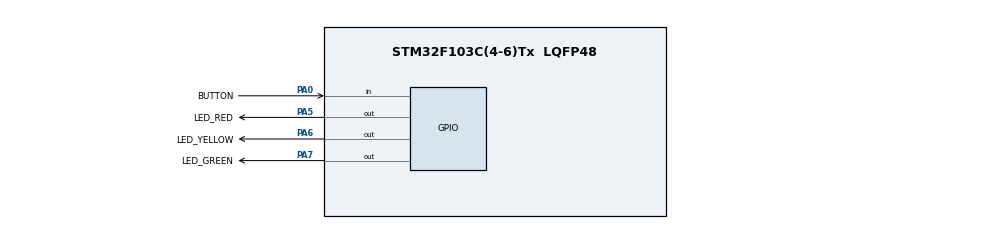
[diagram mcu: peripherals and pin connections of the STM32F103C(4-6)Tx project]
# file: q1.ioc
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Mcu.Family=STM32F1
Mcu.Name=STM32F103C(4-6)Tx
Mcu.Package=LQFP48
NVIC.PriorityGroup=NVIC_PRIORITYGROUP_4
PA0-WKUP.GPIO_Label=BUTTON
PA0-WKUP.Signal=GPIO_Input
PA5.GPIO_Label=LED_RED
PA5.Signal=GPIO_Output
PA6.GPIO_Label=LED_YELLOW
PA6.Signal=GPIO_Output
PA7.GPIO_Label=LED_GREEN
PA7.Signal=GPIO_Output
ProjectManager.HeapSize=0x200
ProjectManager.StackSize=0x400
ProjectManager.TargetToolchain=STM32CubeIDE
RCC.AHBCLKDivider=RCC_SYSCLK_DIV2
RCC.AHBFreq_Value=10000000
RCC.APB1Freq_Value=10000000
RCC.APB1TimFreq_Value=10000000
RCC.APB2Freq_Value=10000000
RCC.APB2TimFreq_Value=10000000
RCC.HCLKFreq_Value=10000000
RCC.PLLMUL=RCC_PLL_MUL5
RCC.SYSCLKFreq_VALUE=20000000
RCC.SYSCLKSource=RCC_SYSCLKSOURCE_PLLCLK
RCC.USBFreq_Value=20000000
board=custom

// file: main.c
/* USER CODE BEGIN Header */
/**
  ******************************************************************************
  * @file           : main.c
  * @brief          : Main program body
  ******************************************************************************
  * @attention
  *
  * Copyright (c) 2025 STMicroelectronics.
  * All rights reserved.
  *
  * This software is licensed under terms that can be found in the LICENSE file
  * in the root directory of this software component.
  * If no LICENSE file comes with this software, it is provided AS-IS.
  *
  ******************************************************************************
  */
/* USER CODE END Header */
#include "main.h"

void SystemClock_Config(void);
static void MX_GPIO_Init(void);

int main(void)
{

  /* MCU Configuration--------------------------------------------------------*/

  /* Reset of all peripherals, Initializes the Flash interface and the Systick. */
  HAL_Init();

  /* Configure the system clock */
  SystemClock_Config();

  /* Initialize all configured peripherals */
  MX_GPIO_Init();
  /* USER CODE BEGIN 2 */

  	uint8_t led_state = 0;
  	uint8_t button_pressed = 0;
  	uint8_t last_button_state = 1;

  /* USER CODE END 2 */

  /* Infinite loop */
  while (1)
  {
	  uint8_t current_button_state = HAL_GPIO_ReadPin(GPIOA, GPIO_PIN_0);

	    		if (current_button_state == 0 && last_button_state == 1)
	    		{
	    			button_pressed = 1;
	    		}
	    		last_button_state = current_button_state;

	    		if (button_pressed)
	    		{
	    			button_pressed = 0;
	    			led_state = (led_state + 1) % 3;

	    			HAL_GPIO_WritePin(GPIOA, GPIO_PIN_5 | GPIO_PIN_6 | GPIO_PIN_7, GPIO_PIN_RESET);

	    			switch (led_state)
	    			{
	    			case 0:
	    				HAL_GPIO_WritePin(GPIOA, GPIO_PIN_5, GPIO_PIN_SET);
	    				break;
	    			case 1:
	    				HAL_GPIO_WritePin(GPIOA, GPIO_PIN_7, GPIO_PIN_SET);
	    				break;
	    			case 2:
	    				HAL_GPIO_WritePin(GPIOA, GPIO_PIN_6, GPIO_PIN_SET);
	    				break;
	    			}
	    		}
	    		HAL_Delay(10);
	    	}
}

void SystemClock_Config(void)
{
  RCC_OscInitTypeDef RCC_OscInitStruct = {0};
  RCC_ClkInitTypeDef RCC_ClkInitStruct = {0};

  /** Initializes the RCC Oscillators according to the specified parameters
  * in the RCC_OscInitTypeDef structure.
  */
  RCC_OscInitStruct.OscillatorType = RCC_OSCILLATORTYPE_HSI;
  RCC_OscInitStruct.HSIState = RCC_HSI_ON;
  RCC_OscInitStruct.HSICalibrationValue = RCC_HSICALIBRATION_DEFAULT;
  RCC_OscInitStruct.PLL.PLLState = RCC_PLL_NONE;
  if (HAL_RCC_OscConfig(&RCC_OscInitStruct) != HAL_OK)
  {
    Error_Handler();
  }

  /** Initializes the CPU, AHB and APB buses clocks
  */
  RCC_ClkInitStruct.ClockType = RCC_CLOCKTYPE_HCLK|RCC_CLOCKTYPE_SYSCLK
                              |RCC_CLOCKTYPE_PCLK1|RCC_CLOCKTYPE_PCLK2;
  RCC_ClkInitStruct.SYSCLKSource = RCC_SYSCLKSOURCE_HSI;
  RCC_ClkInitStruct.AHBCLKDivider = RCC_SYSCLK_DIV1;
  RCC_ClkInitStruct.APB1CLKDivider = RCC_HCLK_DIV1;
  RCC_ClkInitStruct.APB2CLKDivider = RCC_HCLK_DIV1;

  if (HAL_RCC_ClockConfig(&RCC_ClkInitStruct, FLASH_LATENCY_0) != HAL_OK)
  {
    Error_Handler();
  }
}

static void MX_GPIO_Init(void)
{
  GPIO_InitTypeDef GPIO_InitStruct = {0};

  /* GPIO Ports Clock Enable */
  __HAL_RCC_GPIOA_CLK_ENABLE();

  /*Configure GPIO pin Output Level */
  HAL_GPIO_WritePin(GPIOA, LED_RED_Pin|LED_YELLOW_Pin|LED_GREEN_Pin, GPIO_PIN_RESET);

  /*Configure GPIO pin : BUTTON_Pin */
  GPIO_InitStruct.Pin = BUTTON_Pin;
  GPIO_InitStruct.Mode = GPIO_MODE_INPUT;
  GPIO_InitStruct.Pull = GPIO_PULLUP;
  HAL_GPIO_Init(BUTTON_GPIO_Port, &GPIO_InitStruct);

  /*Configure GPIO pins : LED_RED_Pin LED_YELLOW_Pin LED_GREEN_Pin */
  GPIO_InitStruct.Pin = LED_RED_Pin|LED_YELLOW_Pin|LED_GREEN_Pin;
  GPIO_InitStruct.Mode = GPIO_MODE_OUTPUT_PP;
  GPIO_InitStruct.Pull = GPIO_NOPULL;
  GPIO_InitStruct.Speed = GPIO_SPEED_FREQ_LOW;
  HAL_GPIO_Init(GPIOA, &GPIO_InitStruct);

}

void Error_Handler(void)
{
  __disable_irq();
  while (1)
  {
  }
}
